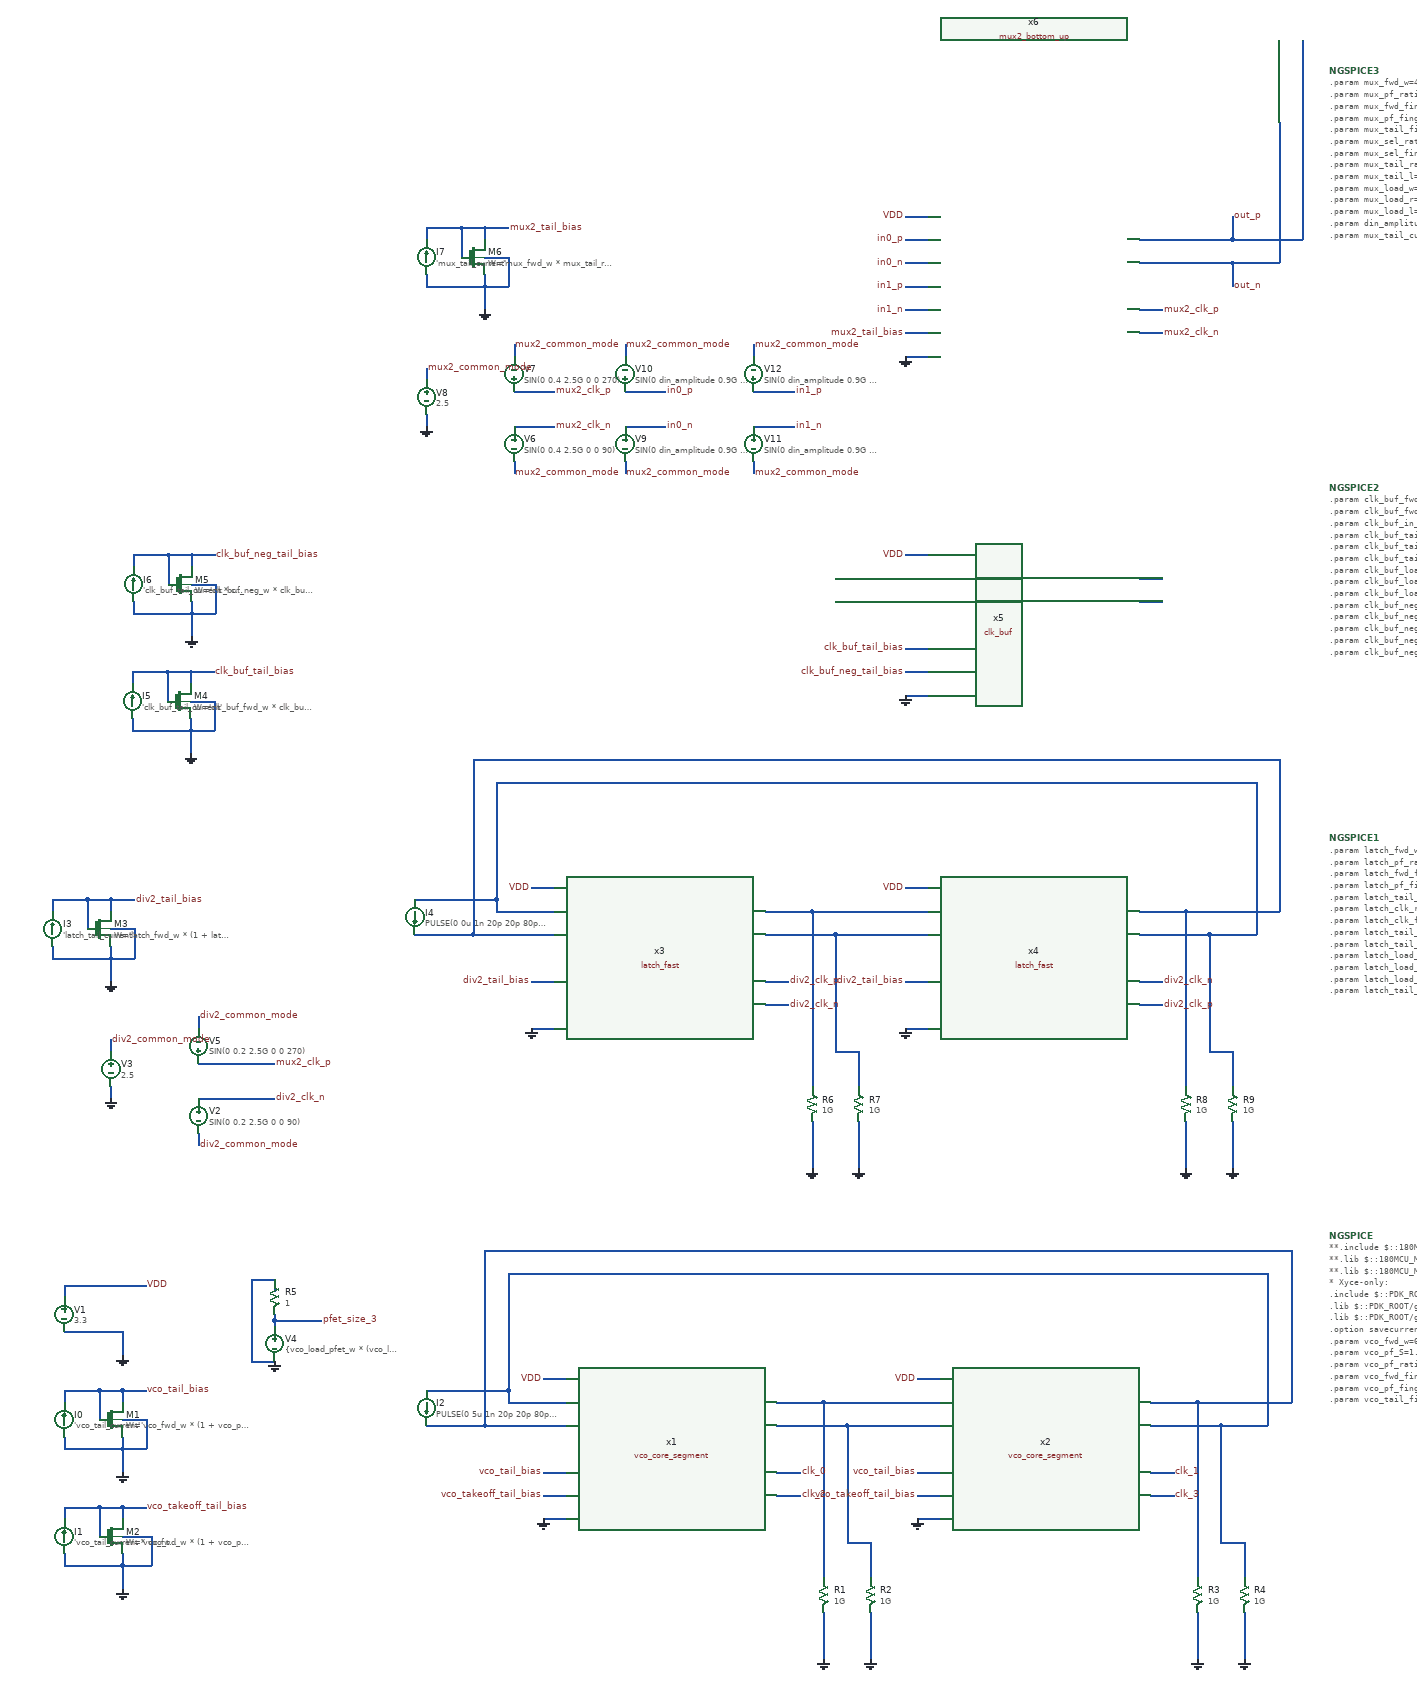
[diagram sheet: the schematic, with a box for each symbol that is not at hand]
v {xschem version=3.4.8RC file_version=1.3}
G {}
K {}
V {}
S {}
F {}
E {}
B 2 -1500 40 760 660 {flags=graph
y1=0.958
y2=5.028
ypos1=0
ypos2=2
divy=5
subdivy=1
unity=1
x1=-1.25e-08
x2=3.75e-08
divx=5
subdivx=1
xlabmag=1.0
ylabmag=1.0
node="clk_0
clk_2
\\"measured; clk_0 clk_2 -\\""
color="4 5 6"
dataset=-1
unitx=1
logx=0
logy=0
hilight_wave=-1
autoload=0
sim_type=table
}
N -540 -500 -500 -500 {lab=VDD}
N 100 -500 140 -500 {lab=VDD}
N 100 -260 140 -260 {lab=0}
N -600 -460 -500 -460 {lab=#net1}
N -600 -480 -600 -460 {lab=#net1}
N 700 -680 700 -420 {lab=#net1}
N 580 -460 740 -460 {lab=#net2}
N -600 -680 700 -680 {lab=#net1}
N 620 -420 700 -420 {lab=#net1}
N 740 -720 740 -460 {lab=#net2}
N -640 -720 740 -720 {lab=#net2}
N -640 -720 -640 -420 {lab=#net2}
N -640 -420 -500 -420 {lab=#net2}
N -60 -460 140 -460 {lab=#net3}
N -20 -420 140 -420 {lab=#net4}
N -140 -340 -100 -340 {lab=clk_0}
N -140 -300 -100 -300 {lab=clk_2}
N 500 -340 540 -340 {lab=clk_1}
N 500 -300 540 -300 {lab=clk_3}
N -540 -340 -500 -340 {lab=vco_tail_bias}
N -540 -300 -500 -300 {lab=vco_takeoff_tail_bias}
N 100 -340 140 -340 {lab=vco_tail_bias}
N 100 -300 140 -300 {lab=vco_takeoff_tail_bias}
N -1260 -480 -1220 -480 {lab=vco_tail_bias}
N -1300 -480 -1260 -480 {lab=vco_tail_bias}
N -1300 -480 -1300 -430 {lab=vco_tail_bias}
N -1260 -480 -1260 -460 {lab=vco_tail_bias}
N -1260 -180 -1260 -140 {lab=0}
N -1260 -280 -1220 -280 {lab=vco_takeoff_tail_bias}
N -1300 -280 -1260 -280 {lab=vco_takeoff_tail_bias}
N -1300 -280 -1300 -230 {lab=vco_takeoff_tail_bias}
N -1260 -280 -1260 -260 {lab=vco_takeoff_tail_bias}
N -1360 -180 -1260 -180 {lab=0}
N -1360 -280 -1300 -280 {lab=vco_takeoff_tail_bias}
N -1360 -280 -1360 -260 {lab=vco_takeoff_tail_bias}
N -1360 -480 -1300 -480 {lab=vco_tail_bias}
N -1360 -480 -1360 -460 {lab=vco_tail_bias}
N -1360 -660 -1220 -660 {lab=VDD}
N -1360 -660 -1360 -640 {lab=VDD}
N -1360 -380 -1260 -380 {lab=0}
N -1260 -380 -1260 -340 {lab=0}
N -1260 -380 -1220 -380 {lab=0}
N -1220 -430 -1220 -380 {lab=0}
N -1260 -430 -1220 -430 {lab=0}
N -1260 -230 -1210 -230 {lab=0}
N -1210 -230 -1210 -180 {lab=0}
N -1260 -180 -1210 -180 {lab=0}
N -740 -420 -640 -420 {lab=#net2}
N -740 -480 -600 -480 {lab=#net1}
N -600 -680 -600 -480 {lab=#net1}
N -60 -100 -60 -20 {lab=0}
N 20 -100 20 -20 {lab=0}
N 20 -220 20 -160 {lab=#net4}
N -60 -460 -60 -160 {lab=#net3}
N -20 -220 20 -220 {lab=#net4}
N -20 -420 -20 -220 {lab=#net4}
N -1360 -400 -1360 -380 {lab=0}
N -1260 -400 -1260 -380 {lab=0}
N -1260 -200 -1260 -180 {lab=0}
N -1360 -200 -1360 -180 {lab=0}
N 580 -100 580 -20 {lab=0}
N 660 -100 660 -20 {lab=0}
N 660 -220 660 -160 {lab=#net1}
N 580 -460 580 -160 {lab=#net2}
N 620 -220 660 -220 {lab=#net1}
N 620 -420 620 -220 {lab=#net1}
N -140 -460 -60 -460 {lab=#net3}
N -140 -420 -20 -420 {lab=#net4}
N 500 -460 580 -460 {lab=#net2}
N 500 -420 620 -420 {lab=#net1}
N -1040 -670 -1000 -670 {lab=0}
N -1040 -530 -1000 -530 {lab=0}
N -1000 -670 -1000 -650 {lab=0}
N -1000 -600 -1000 -590 {lab=pfet_size_3}
N -1040 -670 -1040 -530 {lab=0}
N -1000 -600 -920 -600 {lab=pfet_size_3}
N -1000 -610 -1000 -600 {lab=pfet_size_3}
N -540 -260 -500 -260 {lab=0}
N -1360 -580 -1260 -580 {lab=0}
N -1260 -580 -1260 -540 {lab=0}
N -560 -1100 -520 -1100 {lab=0}
N -560 -1340 -520 -1340 {lab=VDD}
N 80 -1340 120 -1340 {lab=VDD}
N 80 -1100 120 -1100 {lab=0}
N -620 -1300 -520 -1300 {lab=#net5}
N -620 -1320 -620 -1300 {lab=#net5}
N 680 -1520 680 -1260 {lab=#net5}
N 560 -1300 720 -1300 {lab=#net6}
N -620 -1520 680 -1520 {lab=#net5}
N 600 -1260 680 -1260 {lab=#net5}
N 720 -1560 720 -1300 {lab=#net6}
N -660 -1560 720 -1560 {lab=#net6}
N -660 -1560 -660 -1260 {lab=#net6}
N -660 -1260 -520 -1260 {lab=#net6}
N -80 -1300 120 -1300 {lab=#net7}
N -40 -1260 120 -1260 {lab=#net8}
N -160 -1180 -120 -1180 {lab=div2_clk_p}
N -160 -1140 -120 -1140 {lab=div2_clk_n}
N 480 -1180 520 -1180 {lab=div2_clk_n}
N 480 -1140 520 -1140 {lab=div2_clk_p}
N -560 -1180 -520 -1180 {lab=div2_tail_bias}
N 80 -1180 120 -1180 {lab=div2_tail_bias}
N -1280 -1320 -1240 -1320 {lab=div2_tail_bias}
N -1320 -1320 -1280 -1320 {lab=div2_tail_bias}
N -1320 -1320 -1320 -1270 {lab=div2_tail_bias}
N -1280 -1320 -1280 -1300 {lab=div2_tail_bias}
N -1380 -1320 -1320 -1320 {lab=div2_tail_bias}
N -1380 -1320 -1380 -1300 {lab=div2_tail_bias}
N -1380 -1220 -1280 -1220 {lab=0}
N -1280 -1220 -1280 -1180 {lab=0}
N -1280 -1220 -1240 -1220 {lab=0}
N -1240 -1270 -1240 -1220 {lab=0}
N -1280 -1270 -1240 -1270 {lab=0}
N -760 -1260 -660 -1260 {lab=#net6}
N -760 -1320 -620 -1320 {lab=#net5}
N -620 -1520 -620 -1320 {lab=#net5}
N -80 -940 -80 -860 {lab=0}
N 0 -940 0 -860 {lab=0}
N 0 -1060 0 -1000 {lab=#net8}
N -80 -1300 -80 -1000 {lab=#net7}
N -40 -1060 0 -1060 {lab=#net8}
N -40 -1260 -40 -1060 {lab=#net8}
N -1380 -1240 -1380 -1220 {lab=0}
N -1280 -1240 -1280 -1220 {lab=0}
N 560 -940 560 -860 {lab=0}
N 640 -940 640 -860 {lab=0}
N 640 -1060 640 -1000 {lab=#net5}
N 560 -1300 560 -1000 {lab=#net6}
N 600 -1060 640 -1060 {lab=#net5}
N 600 -1260 600 -1060 {lab=#net5}
N -160 -1300 -80 -1300 {lab=#net7}
N -160 -1260 -40 -1260 {lab=#net8}
N 480 -1300 560 -1300 {lab=#net6}
N 480 -1260 600 -1260 {lab=#net5}
N -1130 -920 -1130 -900 {lab=div2_common_mode}
N -1130 -1120 -1130 -1100 {lab=div2_common_mode}
N -1130 -1040 -1000 -1040 {lab=mux2_clk_p}
N -1130 -980 -1000 -980 {lab=div2_clk_n}
N -1280 -1080 -1280 -1060 {lab=div2_common_mode}
N -1280 -1000 -1280 -980 {lab=0}
N 80 -1670 120 -1670 {lab=0}
N 80 -1910 120 -1910 {lab=VDD}
N 80 -1750 120 -1750 {lab=clk_buf_tail_bias}
N -1143.305878170165 -1710 -1103.305878170165 -1710 {lab=clk_buf_tail_bias}
N -1183.305878170165 -1710 -1143.305878170165 -1710 {lab=clk_buf_tail_bias}
N -1183.305878170165 -1710 -1183.305878170165 -1660 {lab=clk_buf_tail_bias}
N -1143.305878170165 -1710 -1143.305878170165 -1690 {lab=clk_buf_tail_bias}
N -1243.305878170165 -1710 -1183.305878170165 -1710 {lab=clk_buf_tail_bias}
N -1243.305878170165 -1710 -1243.305878170165 -1690 {lab=clk_buf_tail_bias}
N -1243.305878170165 -1610 -1143.305878170165 -1610 {lab=0}
N -1143.305878170165 -1610 -1143.305878170165 -1570 {lab=0}
N -1143.305878170165 -1610 -1103.305878170165 -1610 {lab=0}
N -1103.305878170165 -1660 -1103.305878170165 -1610 {lab=0}
N -1143.305878170165 -1660 -1103.305878170165 -1660 {lab=0}
N -1243.305878170165 -1630 -1243.305878170165 -1610 {lab=0}
N -1143.305878170165 -1630 -1143.305878170165 -1610 {lab=0}
N 480 -1870 520 -1870 {lab=#net9}
N 480 -1830 520 -1830 {lab=#net10}
N -40 -1830 120 -1830 {lab=#net11}
N -40 -1870 120 -1870 {lab=#net12}
N -1141.691137783629 -1910 -1101.691137783629 -1910 {lab=clk_buf_neg_tail_bias}
N -1181.691137783629 -1910 -1141.691137783629 -1910 {lab=clk_buf_neg_tail_bias}
N -1181.691137783629 -1910 -1181.691137783629 -1860 {lab=clk_buf_neg_tail_bias}
N -1141.691137783629 -1910 -1141.691137783629 -1890 {lab=clk_buf_neg_tail_bias}
N -1241.691137783629 -1910 -1181.691137783629 -1910 {lab=clk_buf_neg_tail_bias}
N -1241.691137783629 -1910 -1241.691137783629 -1890 {lab=clk_buf_neg_tail_bias}
N -1241.691137783629 -1810 -1141.691137783629 -1810 {lab=0}
N -1141.691137783629 -1810 -1141.691137783629 -1770 {lab=0}
N -1141.691137783629 -1810 -1101.691137783629 -1810 {lab=0}
N -1101.691137783629 -1860 -1101.691137783629 -1810 {lab=0}
N -1141.691137783629 -1860 -1101.691137783629 -1860 {lab=0}
N -1241.691137783629 -1830 -1241.691137783629 -1810 {lab=0}
N -1141.691137783629 -1830 -1141.691137783629 -1810 {lab=0}
N 80 -1710 120 -1710 {lab=clk_buf_neg_tail_bias}
N 80 -2250 120 -2250 {lab=0}
N 80 -2490 120 -2490 {lab=VDD}
N 480 -2330 520 -2330 {lab=mux2_clk_p}
N 480 -2290 520 -2290 {lab=mux2_clk_n}
N 80 -2290 120 -2290 {lab=mux2_tail_bias}
N -640 -2470 -600 -2470 {lab=mux2_tail_bias}
N -680 -2470 -640 -2470 {lab=mux2_tail_bias}
N -680 -2470 -680 -2420 {lab=mux2_tail_bias}
N -640 -2470 -640 -2450 {lab=mux2_tail_bias}
N -740 -2470 -680 -2470 {lab=mux2_tail_bias}
N -740 -2470 -740 -2450 {lab=mux2_tail_bias}
N -740 -2370 -640 -2370 {lab=0}
N -640 -2370 -640 -2330 {lab=0}
N -640 -2370 -600 -2370 {lab=0}
N -600 -2420 -600 -2370 {lab=0}
N -640 -2420 -600 -2420 {lab=0}
N -740 -2390 -740 -2370 {lab=0}
N -640 -2390 -640 -2370 {lab=0}
N 640 -2450 760 -2450 {lab=out_p}
N 640 -2410 720 -2410 {lab=out_n}
N -590 -2070 -590 -2050 {lab=mux2_common_mode}
N -590 -2270 -590 -2250 {lab=mux2_common_mode}
N -740 -2230 -740 -2210 {lab=mux2_common_mode}
N -740 -2150 -740 -2130 {lab=0}
N 720 -2650 720 -2410 {lab=out_n}
N 760 -2790 760 -2450 {lab=out_p}
N -400 -2070 -400 -2050 {lab=mux2_common_mode}
N -400 -2270 -400 -2250 {lab=mux2_common_mode}
N -590 -2190 -520 -2190 {lab=mux2_clk_p}
N -590 -2130 -520 -2130 {lab=mux2_clk_n}
N -400 -2190 -330 -2190 {lab=in0_p}
N -400 -2130 -330 -2130 {lab=in0_n}
N -180 -2070 -180 -2050 {lab=mux2_common_mode}
N -180 -2270 -180 -2250 {lab=mux2_common_mode}
N -180 -2190 -110 -2190 {lab=in1_p}
N -180 -2130 -110 -2130 {lab=in1_n}
N 80 -2450 120 -2450 {lab=in0_p}
N 80 -2410 120 -2410 {lab=in0_n}
N 80 -2370 120 -2370 {lab=in1_p}
N 80 -2330 120 -2330 {lab=in1_n}
N 640 -2410 640 -2370 {lab=out_n}
N 480 -2410 640 -2410 {lab=out_n}
N 640 -2490 640 -2450 {lab=out_p}
N 480 -2450 640 -2450 {lab=out_p}
C {code_shown.sym} 805 -745 0 0 {name=NGSPICE only_toplevel=true format="tcleval( @value )" value="
**.include $::180MCU_MODELS/design.ngspice
**.lib $::180MCU_MODELS/sm141064.ngspice typical
**.lib $::180MCU_MODELS/sm141064.ngspice res_typical

* Xyce-only:
.include $::PDK_ROOT/gf180mcuD/libs.tech/xyce/design.xyce
.lib $::PDK_ROOT/gf180mcuD/libs.tech/xyce/sm141064.xyce typical
.lib $::PDK_ROOT/gf180mcuD/libs.tech/xyce/sm141064.xyce res_typical


.option savecurrents

.param vco_fwd_w=6u
.param vco_pf_S=1.5
.param vco_pf_ratio='1/vco_pf_S'
.param vco_fwd_fingers=2
.param vco_pf_fingers=1
.param vco_tail_fingers=6
.param vco_takeoff_tail_fingers=1
.param vco_takeoff_ratio=0.1
.param vco_takeoff_fingers=1
.param vco_tail_ratio=5
.param vco_tail_l=1u
.param vco_takeoff_tail_ratio=5
.param vco_takeoff_tail_l=1u
.param vco_load_w=1u
.param vco_load_r=4k
.param vco_load_l='vco_load_r/1000 * vco_load_w'
.param vco_load_pfet_w=0.22u
.param vco_load_pfet_l=0.7u
.param vco_load_pfet_scale_base=2.0
.param vco_takeoff_load_adjust=1
.param vco_takeoff_load_w=1u
.param vco_takeoff_load_r='(vco_load_r / vco_takeoff_ratio) * vco_takeoff_load_adjust'
.param vco_takeoff_load_l='vco_takeoff_load_r/1000 * vco_takeoff_load_w'
.param vco_takeoff_tail_adjust=1
.param vco_tail_current=128u

.param vco_load_pfet_code='30'
.param vco_load_pfet_bit_0='vco_load_pfet_code % 2'
.param vco_load_pfet_bit_1='int(vco_load_pfet_code / 2) % 2'
.param vco_load_pfet_bit_2='int(vco_load_pfet_code / 4) % 2'
.param vco_load_pfet_bit_3='int(vco_load_pfet_code / 8) % 2'
.param vco_load_pfet_bit_4='int(vco_load_pfet_code / 16) % 2'

*.print \{vco_load_pfet_w * (vco_load_pfet_scale_base**4)\}
* PSS analysis unavailable in the normally distributed/available ngspice version/build, at least for now, so don't use it!
*.pss gfreq tstab oscnob psspoints harms sciter=50 steadycoeff=1e-3 <uic>
*.param harms=20
*.pss 1G 5n clk_0 5*harms 20
* looks like params there might not work? Let's expand manually:
*.pss 1G 5n clk_0 100 20


*Xyce-only:
.TRAN 100p 50n
.MEASURE TRAN output_freq FREQ V(clk_0, clk_2) TD=20n
.MEASURE TRAN vco_load_pfet_code EQN\{vco_load_pfet_code\}
.MEASURE TRAN vco_tail_current EQN\{vco_tail_current\}
*.PRINT TRAN FORMAT=raw file=vco_core_tb.raw v(*) i(*)

* First we test a very condensed run, before we put the effort in for the full large one.
*.STEP OCT vco_tail_current 64u 256u 3
*.STEP vco_load_pfet_code 1 10 3

.STEP OCT vco_tail_current 4u 1024u 3
.STEP vco_load_pfet_code 1 31 1

**.control
**save all
*save sub
*save internals
*show
*op
*run
**tran 5p 50n
**plot v(clk_0) v(clk_1) v(clk_2) v(clk_3)
**plot net1 net2 net3 net4 x1.net1
**write vco_core_tb.raw all
**.endc
"}
C {vco_core_segment.sym} -320 -380 0 0 {name=x1}
C {symbols/nfet_03v3.sym} -1280 -430 0 0 {name=M1
L="'vco_tail_l'"
W="'vco_fwd_w * (1 + vco_pf_ratio) * vco_tail_ratio'"
nf="'vco_tail_fingers'"
m=1
ad="'int((nf+1)/2) * W/nf * 0.18u'"
pd="'2*int((nf+1)/2) * (W/nf + 0.18u)'"
as="'int((nf+2)/2) * W/nf * 0.18u'"
ps="'2*int((nf+2)/2) * (W/nf + 0.18u)'"
nrd="'0.18u / W'" nrs="'0.18u / W'"
sa=0 sb=0 sd=0
model=nfet_03v3
spiceprefix=X
}
C {vco_core_segment.sym} 320 -380 0 0 {name=x2}
C {symbols/nfet_03v3.sym} -1280 -230 0 0 {name=M2
L="'vco_takeoff_tail_l'"
W="'vco_fwd_w * (1 + vco_pf_ratio) * vco_tail_ratio * vco_takeoff_ratio'"
nf="'vco_takeoff_tail_fingers'"
m=1
ad="'int((nf+1)/2) * W/nf * 0.18u'"
pd="'2*int((nf+1)/2) * (W/nf + 0.18u)'"
as="'int((nf+2)/2) * W/nf * 0.18u'"
ps="'2*int((nf+2)/2) * (W/nf + 0.18u)'"
nrd="'0.18u / W'" nrs="'0.18u / W'"
sa=0 sb=0 sd=0
model=nfet_03v3
spiceprefix=X
}
C {lab_wire.sym} -540 -500 0 0 {name=p1 sig_type=std_logic lab=VDD}
C {lab_wire.sym} 100 -500 0 0 {name=p2 sig_type=std_logic lab=VDD}
C {lab_wire.sym} -100 -340 0 1 {name=p5 sig_type=std_logic lab=clk_0}
C {lab_wire.sym} -100 -300 0 1 {name=p6 sig_type=std_logic lab=clk_2}
C {lab_wire.sym} 540 -340 0 1 {name=p7 sig_type=std_logic lab=clk_1}
C {lab_wire.sym} 540 -300 0 1 {name=p8 sig_type=std_logic lab=clk_3}
C {lab_wire.sym} -540 -340 0 0 {name=p9 sig_type=std_logic lab="vco_tail_bias"}
C {lab_wire.sym} -540 -300 0 0 {name=p10 sig_type=std_logic lab="vco_takeoff_tail_bias"}
C {lab_wire.sym} 100 -340 0 0 {name=p11 sig_type=std_logic lab="vco_tail_bias"}
C {lab_wire.sym} 100 -300 0 0 {name=p12 sig_type=std_logic lab="vco_takeoff_tail_bias"}
C {lab_wire.sym} -1220 -480 0 1 {name=p13 sig_type=std_logic lab="vco_tail_bias"}
C {lab_wire.sym} -1220 -280 0 1 {name=p16 sig_type=std_logic lab="vco_takeoff_tail_bias"}
C {vsource.sym} -1360 -610 0 1 {name=V1 value=3.3 savecurrent=false}
C {isource.sym} -1360 -430 2 0 {name=I0 value="'vco_tail_current'"}
C {isource.sym} -1360 -230 2 0 {name=I1 value="'vco_tail_current * vco_takeoff_ratio * vco_takeoff_tail_adjust'"}
C {lab_wire.sym} -1220 -660 0 1 {name=p18 sig_type=std_logic lab=VDD}
C {isource.sym} -740 -450 0 0 {name=I2 value="PULSE(0 5u 1n 20p 20p 80p 0 1)"}
C {res.sym} -60 -130 0 0 {name=R1
value=1G
footprint=1206
device=resistor
m=1}
C {gnd.sym} -60 -20 0 0 {name=l2 lab=0}
C {res.sym} 20 -130 0 0 {name=R2
value=1G
footprint=1206
device=resistor
m=1}
C {gnd.sym} 20 -20 0 0 {name=l3 lab=0}
C {gnd.sym} -1260 -540 0 0 {name=l1 lab=0}
C {gnd.sym} -1260 -340 0 0 {name=l4 lab=0}
C {gnd.sym} -1260 -140 0 0 {name=l5 lab=0}
C {gnd.sym} -540 -260 0 0 {name=l6 lab=0}
C {gnd.sym} 100 -260 0 0 {name=l7 lab=0}
C {res.sym} 580 -130 0 0 {name=R3
value=1G
footprint=1206
device=resistor
m=1}
C {gnd.sym} 580 -20 0 0 {name=l8 lab=0}
C {res.sym} 660 -130 0 0 {name=R4
value=1G
footprint=1206
device=resistor
m=1}
C {gnd.sym} 660 -20 0 0 {name=l9 lab=0}
C {vsource.sym} -1000 -560 0 0 {name=V4 value="\{vco_load_pfet_w * (vco_load_pfet_scale_base^3)\}"}
C {res.sym} -1000 -640 0 0 {name=R5
value=1
footprint=1206
device=resistor
m=1}
C {lab_wire.sym} -920 -600 0 1 {name=p3 sig_type=std_logic lab=pfet_size_3}
C {gnd.sym} -1000 -530 0 0 {name=l10 lab=0}
C {code_shown.sym} 805 -1425 0 0 {name=NGSPICE1 only_toplevel=true format="tcleval( @value )" value="
.param latch_fwd_w=2u
.param latch_pf_ratio='1'
.param latch_fwd_fingers=1
.param latch_pf_fingers=1
.param latch_tail_fingers=20
.param latch_clk_ratio=0.5
.param latch_clk_fingers=1
.param latch_tail_ratio=50
.param latch_tail_l=1u
.param latch_load_w=1u
.param latch_load_r=12k
.param latch_load_l='latch_load_r/1000 * latch_load_w'
.param latch_tail_current=64u
"}
C {latch_fast.sym} -340 -1220 0 0 {name=x3}
C {symbols/nfet_03v3.sym} -1300 -1270 0 0 {name=M3
L="'latch_tail_l'"
W="'latch_fwd_w * (1 + latch_pf_ratio) * latch_tail_ratio'"
nf="'latch_tail_fingers'"
m=1
ad="'int((nf+1)/2) * W/nf * 0.18u'"
pd="'2*int((nf+1)/2) * (W/nf + 0.18u)'"
as="'int((nf+2)/2) * W/nf * 0.18u'"
ps="'2*int((nf+2)/2) * (W/nf + 0.18u)'"
nrd="'0.18u / W'" nrs="'0.18u / W'"
sa=0 sb=0 sd=0
model=nfet_03v3
spiceprefix=X
}
C {latch_fast.sym} 300 -1220 0 0 {name=x4}
C {lab_wire.sym} -560 -1340 0 0 {name=p4 sig_type=std_logic lab=VDD}
C {lab_wire.sym} 80 -1340 0 0 {name=p14 sig_type=std_logic lab=VDD}
C {lab_wire.sym} -120 -1180 0 1 {name=p15 sig_type=std_logic lab=div2_clk_p}
C {lab_wire.sym} -120 -1140 0 1 {name=p17 sig_type=std_logic lab=div2_clk_n}
C {lab_wire.sym} 520 -1180 0 1 {name=p19 sig_type=std_logic lab=div2_clk_n}
C {lab_wire.sym} 520 -1140 0 1 {name=p20 sig_type=std_logic lab=div2_clk_p}
C {lab_wire.sym} -560 -1180 0 0 {name=p21 sig_type=std_logic lab=div2_tail_bias}
C {lab_wire.sym} 80 -1180 0 0 {name=p22 sig_type=std_logic lab=div2_tail_bias}
C {lab_wire.sym} -1240 -1320 0 1 {name=p23 sig_type=std_logic lab=div2_tail_bias}
C {isource.sym} -1380 -1270 2 0 {name=I3 value="'latch_tail_current'"}
C {isource.sym} -760 -1290 0 0 {name=I4 value="PULSE(0 0u 1n 20p 20p 80p 0 1)"}
C {res.sym} -80 -970 0 0 {name=R6
value=1G
footprint=1206
device=resistor
m=1}
C {gnd.sym} -80 -860 0 0 {name=l11 lab=0}
C {res.sym} 0 -970 0 0 {name=R7
value=1G
footprint=1206
device=resistor
m=1}
C {gnd.sym} 0 -860 0 0 {name=l12 lab=0}
C {gnd.sym} -1280 -1180 0 0 {name=l13 lab=0}
C {gnd.sym} -560 -1100 0 0 {name=l14 lab=0}
C {gnd.sym} 80 -1100 0 0 {name=l15 lab=0}
C {res.sym} 560 -970 0 0 {name=R8
value=1G
footprint=1206
device=resistor
m=1}
C {gnd.sym} 560 -860 0 0 {name=l16 lab=0}
C {res.sym} 640 -970 0 0 {name=R9
value=1G
footprint=1206
device=resistor
m=1}
C {gnd.sym} 640 -860 0 0 {name=l17 lab=0}
C {vsource.sym} -1130 -950 0 0 {name=V2 value="SIN(0 0.2 2.5G 0 0 90)"}
C {vsource.sym} -1130 -1070 2 1 {name=V5 value="SIN(0 0.2 2.5G 0 0 270)"}
C {lab_wire.sym} -1130 -1120 0 1 {name=p24 sig_type=std_logic lab=div2_common_mode}
C {lab_wire.sym} -1130 -900 2 0 {name=p25 sig_type=std_logic lab=div2_common_mode}
C {lab_wire.sym} -1000 -1040 0 1 {name=p26 sig_type=std_logic lab=mux2_clk_p}
C {lab_wire.sym} -1000 -980 0 1 {name=p27 sig_type=std_logic lab=div2_clk_n}
C {vsource.sym} -1280 -1030 0 1 {name=V3 value=2.5 savecurrent=false}
C {lab_wire.sym} -1280 -1080 0 1 {name=p28 sig_type=std_logic lab=div2_common_mode}
C {gnd.sym} -1280 -980 0 0 {name=l18 lab=0}
C {clk_buf.sym} 300 -1790 0 0 {name=x5}
C {symbols/nfet_03v3.sym} -1163.305878170165 -1660 0 0 {name=M4
L="'clk_buf_tail_l'"
W="'clk_buf_fwd_w * clk_buf_tail_ratio'"
nf="'clk_buf_tail_fingers'"
m=1
ad="'int((nf+1)/2) * W/nf * 0.18u'"
pd="'2*int((nf+1)/2) * (W/nf + 0.18u)'"
as="'int((nf+2)/2) * W/nf * 0.18u'"
ps="'2*int((nf+2)/2) * (W/nf + 0.18u)'"
nrd="'0.18u / W'" nrs="'0.18u / W'"
sa=0 sb=0 sd=0
model=nfet_03v3
spiceprefix=X
}
C {lab_wire.sym} 80 -1910 0 0 {name=p29 sig_type=std_logic lab=VDD}
C {lab_wire.sym} 80 -1750 0 0 {name=p30 sig_type=std_logic lab=clk_buf_tail_bias}
C {lab_wire.sym} -1103.305878170165 -1710 0 1 {name=p31 sig_type=std_logic lab=clk_buf_tail_bias}
C {isource.sym} -1243.305878170165 -1660 2 0 {name=I5 value="'clk_buf_tail_current'"}
C {gnd.sym} -1143.305878170165 -1570 0 0 {name=l19 lab=0}
C {gnd.sym} 80 -1670 0 0 {name=l20 lab=0}
C {symbols/nfet_03v3.sym} -1161.691137783629 -1860 0 0 {name=M5
L="'clk_buf_tail_l'"
W="'clk_buf_neg_w * clk_buf_neg_tail_ratio'"
nf="'clk_buf_tail_fingers'"
m=1
ad="'int((nf+1)/2) * W/nf * 0.18u'"
pd="'2*int((nf+1)/2) * (W/nf + 0.18u)'"
as="'int((nf+2)/2) * W/nf * 0.18u'"
ps="'2*int((nf+2)/2) * (W/nf + 0.18u)'"
nrd="'0.18u / W'" nrs="'0.18u / W'"
sa=0 sb=0 sd=0
model=nfet_03v3
spiceprefix=X
}
C {lab_wire.sym} -1101.691137783629 -1910 0 1 {name=p32 sig_type=std_logic lab=clk_buf_neg_tail_bias}
C {isource.sym} -1241.691137783629 -1860 2 0 {name=I6 value="'clk_buf_tail_current * clk_buf_neg_ratio * clk_buf_neg_tail_adjust'"}
C {gnd.sym} -1141.691137783629 -1770 0 0 {name=l21 lab=0
W="'clk_buf_neg_w * clk_buf_neg_tail_ratio'"}
C {lab_wire.sym} 80 -1710 0 0 {name=p33 sig_type=std_logic lab=clk_buf_neg_tail_bias}
C {code_shown.sym} 805 -2025 0 0 {name=NGSPICE2 only_toplevel=true format="tcleval( @value )" value=".param clk_buf_fwd_w=16u
.param clk_buf_fwd_fingers=2
.param clk_buf_in_out_ratio=0.55
.param clk_buf_tail_fingers=4
.param clk_buf_tail_ratio=4
.param clk_buf_tail_l=1u
.param clk_buf_load_w=2u
.param clk_buf_load_r=4k
.param clk_buf_load_l='clk_buf_load_r/1000 * clk_buf_load_w'
.param clk_buf_neg_ratio='0.155'
.param clk_buf_neg_w='clk_buf_fwd_w * clk_buf_neg_ratio'
.param clk_buf_neg_fingers=1
.param clk_buf_neg_tail_ratio=5
.param clk_buf_neg_tail_adjust=1.5
.param clk_buf_tail_current=512u

.param clk_buf_tb_fan_out=1.78039
.param clk_buf_tb_freq=2.5G"}
C {code_shown.sym} 805 -2738.704612879492 0 0 {name="NGSPICE3" only_toplevel="true" format="tcleval( @value )" value=".param mux_fwd_w=4u
.param mux_pf_ratio='1'
.param mux_fwd_fingers=1
.param mux_pf_fingers=1
.param mux_tail_fingers=20
.param mux_sel_ratio=1
.param mux_sel_fingers=1
.param mux_tail_ratio=50
.param mux_tail_l=1u
.param mux_load_w=1u
.param mux_load_r=12k
.param mux_load_l='mux_load_r/1000 * mux_load_w'
.param din_amplitude=0.4
.param mux_tail_current=128u"}
C {mux2_bottom_up.sym} 300 -2370 0 0 {name=x6}
C {symbols/nfet_03v3.sym} -660 -2420 0 0 {name=M6
L="'mux_tail_l'"
W="'mux_fwd_w * mux_tail_ratio'"
nf="'mux_tail_fingers'"
m=1
ad="'int((nf+1)/2) * W/nf * 0.18u'"
pd="'2*int((nf+1)/2) * (W/nf + 0.18u)'"
as="'int((nf+2)/2) * W/nf * 0.18u'"
ps="'2*int((nf+2)/2) * (W/nf + 0.18u)'"
nrd="'0.18u / W'" nrs="'0.18u / W'"
sa=0 sb=0 sd=0
model=nfet_03v3
spiceprefix=X
}
C {lab_wire.sym} 80 -2490 0 0 {name=p34 sig_type=std_logic lab=VDD}
C {lab_wire.sym} 520 -2330 0 1 {name=p35 sig_type=std_logic lab=mux2_clk_p}
C {lab_wire.sym} 520 -2290 0 1 {name=p36 sig_type=std_logic lab=mux2_clk_n}
C {lab_wire.sym} 80 -2290 0 0 {name=p37 sig_type=std_logic lab=mux2_tail_bias}
C {lab_wire.sym} -600 -2470 0 1 {name=p38 sig_type=std_logic lab=mux2_tail_bias}
C {isource.sym} -740 -2420 2 0 {name=I7 value="'mux_tail_current'"}
C {gnd.sym} -640 -2330 0 0 {name=l22 lab=0}
C {gnd.sym} 80 -2250 0 0 {name=l23 lab=0}
C {vsource.sym} -590 -2100 0 0 {name=V6 value="SIN(0 0.4 2.5G 0 0 90)"}
C {vsource.sym} -590 -2220 2 1 {name=V7 value="SIN(0 0.4 2.5G 0 0 270)"}
C {lab_wire.sym} -590 -2270 0 1 {name=p39 sig_type=std_logic lab=mux2_common_mode}
C {lab_wire.sym} -590 -2050 2 0 {name=p40 sig_type=std_logic lab=mux2_common_mode}
C {lab_wire.sym} -520 -2190 0 1 {name=p41 sig_type=std_logic lab=mux2_clk_p}
C {lab_wire.sym} -520 -2130 0 1 {name=p42 sig_type=std_logic lab=mux2_clk_n}
C {vsource.sym} -740 -2180 0 1 {name=V8 value=2.5 savecurrent=false}
C {lab_wire.sym} -740 -2230 0 1 {name=p43 sig_type=std_logic lab=mux2_common_mode}
C {gnd.sym} -740 -2130 0 0 {name=l24 lab=0}
C {vsource.sym} -400 -2100 0 0 {name=V9 value="SIN(0 din_amplitude 0.9G 0 0 0)"}
C {vsource.sym} -400 -2220 2 1 {name=V10 value="SIN(0 din_amplitude 0.9G 0 0 180)"}
C {lab_wire.sym} -400 -2270 0 1 {name=p44 sig_type=std_logic lab=mux2_common_mode}
C {lab_wire.sym} -400 -2050 2 0 {name=p45 sig_type=std_logic lab=mux2_common_mode}
C {lab_wire.sym} -330 -2190 0 1 {name=p46 sig_type=std_logic lab=in0_p}
C {lab_wire.sym} -330 -2130 0 1 {name=p47 sig_type=std_logic lab=in0_n}
C {vsource.sym} -180 -2100 0 0 {name=V11 value="SIN(0 din_amplitude 0.9G 0 0 90)"}
C {vsource.sym} -180 -2220 2 1 {name=V12 value="SIN(0 din_amplitude 0.9G 0 0 270)"}
C {lab_wire.sym} -180 -2270 0 1 {name=p48 sig_type=std_logic lab=mux2_common_mode}
C {lab_wire.sym} -180 -2050 2 0 {name=p49 sig_type=std_logic lab=mux2_common_mode}
C {lab_wire.sym} -110 -2190 0 1 {name=p50 sig_type=std_logic lab=in1_p}
C {lab_wire.sym} -110 -2130 0 1 {name=p51 sig_type=std_logic lab=in1_n}
C {lab_wire.sym} 80 -2450 0 0 {name=p52 sig_type=std_logic lab=in0_p}
C {lab_wire.sym} 80 -2410 0 0 {name=p53 sig_type=std_logic lab=in0_n}
C {lab_wire.sym} 80 -2370 0 0 {name=p54 sig_type=std_logic lab=in1_p}
C {lab_wire.sym} 80 -2330 0 0 {name=p55 sig_type=std_logic lab=in1_n}
C {lab_wire.sym} 640 -2490 0 1 {name=p56 sig_type=std_logic lab=out_p}
C {lab_wire.sym} 640 -2370 0 1 {name=p57 sig_type=std_logic lab=out_n}
